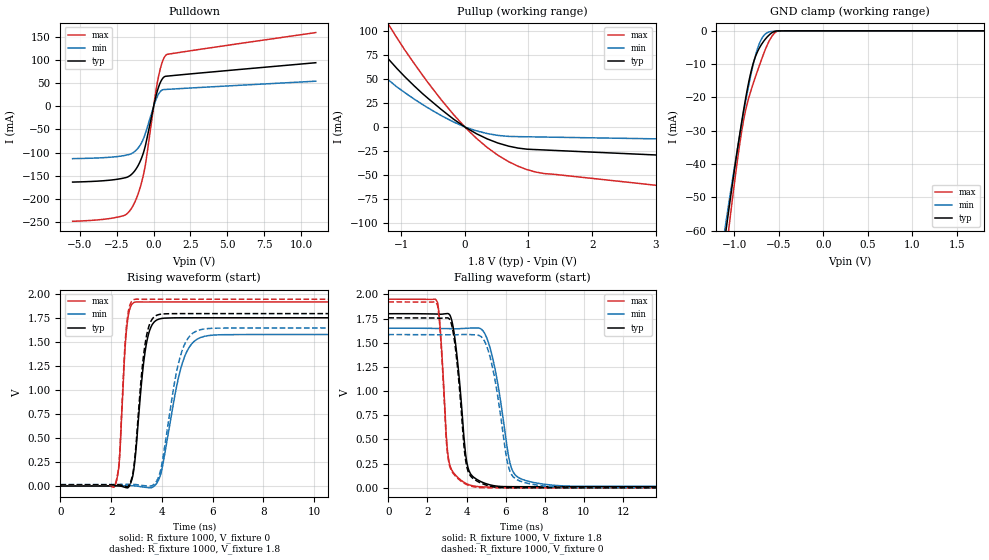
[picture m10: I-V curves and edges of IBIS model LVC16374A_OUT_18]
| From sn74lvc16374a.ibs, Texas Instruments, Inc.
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[Model]   LVC16374A_OUT_18
Model_type  3-state
Enable   Active-Low
Vref =   0
Rref =   1000
Cref =   30p
Vmeas =   0.9
| variable   typ   min   max
C_comp   5.26pF   4.69pF   6.09pF
| C_pullup   6.13pF   5.54pF   6.81pF
| C_pulldown   8.31pF   6.61pF   10.14pF
| C_tri-state   5.26pF   4.69pF   6.09pF
[Temperature Range]   40   100   -40
| Ambient temperature   25   85   -40
[Voltage range]   1.8   1.65   1.95
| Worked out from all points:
|   slope of the pulldown table from 0 to 0.27 V, typ, clamps not added: 7.65 ohm
|   slope of the pullup table from 0 to 0.27 V, typ, clamps not added: 27.4 ohm
|   GND clamp passes 1 mA (typ) near -0.60 V on its own axis
|   rising waveform, R_fixture 1000, V_fixture 0: 20-80 % time 371ps typ, 688ps min, 224ps max; typ from 0 V to 1.76 V
|   falling waveform, R_fixture 1000, V_fixture 1.8: 20-80 % time 474ps typ, 780ps min, 337ps max; typ from 1.8 V to 0.012 V
|   rising waveform, R_fixture 1000, V_fixture 1.8: 20-80 % time 357ps typ, 626ps min, 220ps max; typ from 0.012 V to 1.8 V
|   falling waveform, R_fixture 1000, V_fixture 0: 20-80 % time 458ps typ, 739ps min, 331ps max; typ from 1.76 V to 0 V
[GND Clamp]
| LVC16374A_OUT_18
|   Voltage   I(typ)   I(min)   I(max)
-5.5V     -1.092A    -985.9mA   -1.265A
-1.12V    -65.63mA   -62.5mA    -73.1mA
-1.09V    -59.68mA   -57.14mA   -66.23mA
-1.06V    -53.82mA   -51.86mA   -59.48mA
-1.045V   -50.92mA   -49.25mA   -56.15mA
-960mV    -35.13mA   -34.95mA   -38.34mA
-900mV    -24.87mA   -25.49mA   -27.8mA
-795mV    -10.66mA   -11.13mA   -16.59mA
-735mV    -6.119mA   -5.16mA    -11.82mA
-685mV    -3.765mA   -2.107mA   -8.076mA
-535mV    -84.46uA   -113.4uA   -414.9uA
1.8V      37.82pA    12.26nA    -2.547nA
[Pulldown]
| LVC16374A_OUT_18
|   Voltage   I(typ)   I(min)   I(max)
-5.5V     -163.6mA   -113mA     -248.3mA
-2.075V   -155.2mA   -106.7mA   -236.5mA
-1.745V   -152.2mA   -104.6mA   -230mA
-1.42V    -144.4mA   -100.5mA   -215.8mA
-1.03V    -126.4mA   -88.99mA   -186.9mA
-695mV    -100.2mA   -69.99mA   -148.2mA
-520mV    -79.1mA    -54.01mA   -118mA
70mV      10.47mA    6.993mA    15.91mA
275mV     35.8mA     23.13mA    55.48mA
565mV     58.22mA    35.03mA    93.73mA
855mV     65.08mA    36.56mA    111.2mA
11V       94.21mA    54.33mA    159.3mA
[Pullup]
| LVC16374A_OUT_18
|   Voltage   I(typ)   I(min)   I(max)
-5.5V     75.37mA    20.95mA    195.8mA
-3.75V    234.1mA    38.04mA    389.4mA
-3.41V    238.1mA    55.86mA    355.3mA
-3.285V   230.3mA    96.69mA    342mA
-3.205V   224.9mA    129.9mA    333.3mA
-2.375V   162.9mA    117.7mA    240.2mA
-1.61V    102.9mA    73.43mA    152.8mA
-1.185V   69.47mA    48.03mA    105.1mA
15mV      -631.9uA   -377.7uA   -1.037mA
1.115V    -23.53mA   -10.37mA   -46.86mA
8.41V     -45.64mA   -18.13mA   -100.6mA
11V       -53.91mA   -20.99mA   -120.6mA
[Ramp]
| LVC16374A_OUT_18
| variable   typ   min   max
dV/dt_r   1.07/3.78E-10   0.96/6.97E-10   1.16/2.34E-10
dV/dt_f   1.07/4.77E-10   0.98/7.83E-10   1.17/3.47E-10
R_load = 1000
[Rising Waveform]
| LVC16374A_OUT_18
R_fixture =   1000
C_fixture =   0
L_fixture =   0
V_fixture =   0
V_fixture_min = 0
V_fixture_max = 0
|   Time   V(typ)   V(min)   V(max)
0s        561.2pV    2.27nV     19.09nV
2.155ns   1.743mV    780.3uV    6.911mV
2.315ns   305.8uV    1.234mV    231.8mV
2.625ns   -19.15mV   2.172mV    1.679V
2.99ns    409.5mV    -214.5uV   1.922V
3.3ns     1.326V     -12.02mV   1.921V
3.61ns    1.681V     -15.78mV   1.921V
4.885ns   1.756V     1.342V     1.922V
5.865ns   1.756V     1.571V     1.922V
50ns      1.756V     1.582V     1.922V
[Falling Waveform]
| LVC16374A_OUT_18
R_fixture =   1000
C_fixture =   0
L_fixture =   0
V_fixture =   1.8
V_fixture_min = 1.65
V_fixture_max = 1.95
|   Time   V(typ)   V(min)   V(max)
0s        1.8V       1.65V      1.95V
2.5ns     1.797V     1.647V     1.923V
3.15ns    1.785V     1.646V     233.9mV
3.49ns    1.4V       1.645V     120.1mV
3.98ns    304.4mV    1.649V     44.69mV
4.36ns    110.5mV    1.653V     19.2mV
5.225ns   29.76mV    1.43V      8.825mV
6.32ns    12.32mV    191.9mV    8.431mV
7.58ns    11.7mV     49.38mV    8.364mV
50ns      11.53mV    15.73mV    8.262mV
[Rising Waveform]
| LVC16374A_OUT_18
R_fixture =   1000
C_fixture =   0
L_fixture =   0
V_fixture =   1.8
V_fixture_min = 1.65
V_fixture_max = 1.95
|   Time   V(typ)   V(min)   V(max)
0s        11.51mV    15.68mV    8.257mV
2.16ns    13.06mV    16.41mV    19.29mV
2.315ns   11.51mV    16.76mV    248.6mV
2.615ns   -6.588mV   17.43mV    1.7V
2.925ns   271.8mV    16.26mV    1.949V
3.27ns    1.345V     4.412mV    1.95V
3.565ns   1.718V     -1.06mV    1.95V
4.8ns     1.8V       1.414V     1.95V
5.7ns     1.8V       1.641V     1.95V
50ns      1.8V       1.65V      1.95V
[Falling Waveform]
| LVC16374A_OUT_18
R_fixture =   1000
C_fixture =   0
L_fixture =   0
V_fixture =   0
V_fixture_min = 0
V_fixture_max = 0
|   Time   V(typ)   V(min)   V(max)
0s        1.758V     1.585V     1.922V
2.5ns     1.755V     1.582V     1.894V
3.15ns    1.737V     1.582V     217.8mV
3.475ns   1.364V     1.582V     113.1mV
3.955ns   280.9mV    1.585V     38.37mV
4.36ns    92.59mV    1.582V     10.73mV
5.19ns    18.39mV    1.36V      570.1uV
6.22ns    861.3uV    170.9mV    184.7uV
7.47ns    192.5uV    32.78mV    106.9uV
50ns      12.28uV    45.74uV    5.027uV
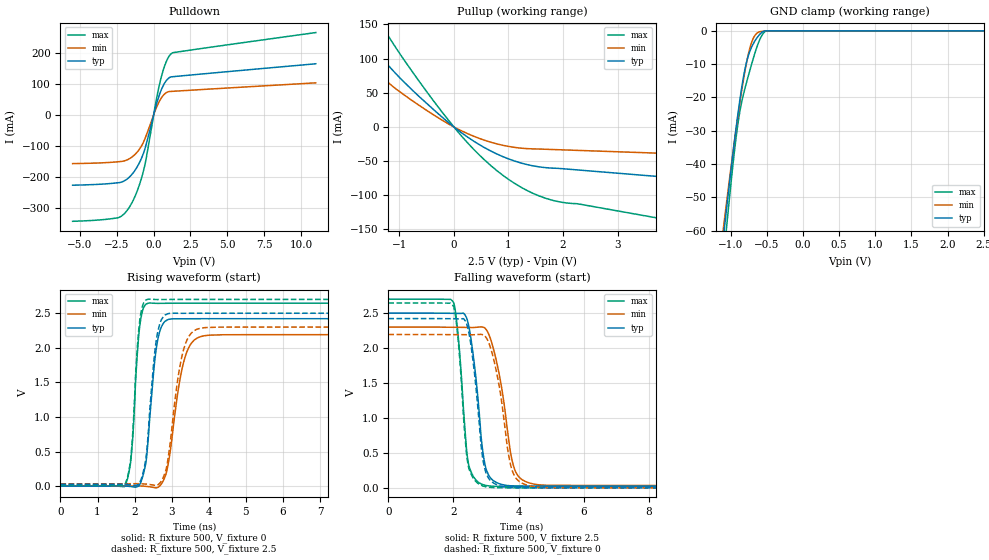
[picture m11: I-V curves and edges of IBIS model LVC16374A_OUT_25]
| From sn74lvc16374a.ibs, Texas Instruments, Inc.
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[Model]   LVC16374A_OUT_25
Model_type  3-state
Enable   Active-Low
Vref =   0
Rref =   500
Cref =   30p
Vmeas =   1.25
| variable   typ   min   max
C_comp   5.07pF   4.45pF   6.04pF
| C_pullup   6.01pF   5.36pF   6.86pF
| C_pulldown   7.61pF   6.28pF   8.94pF
| C_tri-state   5.07pF   4.45pF   6.04pF
[Temperature Range]   40   100   -40
| Ambient temperature   25   85   -40
[Voltage range]   2.5   2.3   2.7
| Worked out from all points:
|   slope of the pulldown table from 0 to 0.375 V, typ, clamps not added: 6 ohm
|   slope of the pullup table from 0 to 0.375 V, typ, clamps not added: 17.5 ohm
|   GND clamp passes 1 mA (typ) near -0.60 V on its own axis
|   rising waveform, R_fixture 500, V_fixture 0: 20-80 % time 236ps typ, 361ps min, 177ps max; typ from 0 V to 2.42 V
|   falling waveform, R_fixture 500, V_fixture 2.5: 20-80 % time 326ps typ, 457ps min, 254ps max; typ from 2.5 V to 0.025 V
|   rising waveform, R_fixture 500, V_fixture 2.5: 20-80 % time 229ps typ, 338ps min, 174ps max; typ from 0.025 V to 2.5 V
|   falling waveform, R_fixture 500, V_fixture 0: 20-80 % time 313ps typ, 429ps min, 250ps max; typ from 2.42 V to 0 V
[GND Clamp]
| LVC16374A_OUT_25
|   Voltage   I(typ)   I(min)   I(max)
-5.5V     -1.092A    -985.9mA   -1.265A
-1.115V   -64.63mA   -61.6mA    -71.95mA
-1.085V   -58.69mA   -56.25mA   -65.09mA
-1.055V   -52.85mA   -50.99mA   -58.36mA
-905mV    -25.68mA   -26.25mA   -28.57mA
-860mV    -18.71mA   -19.61mA   -22.6mA
-795mV    -10.66mA   -11.13mA   -16.59mA
-740mV    -6.406mA   -5.567mA   -12.21mA
-680mV    -3.568mA   -1.9mA     -7.713mA
-600mV    -1.079mA   -275.4uA   -2.703mA
-530mV    -59.09uA   -106.9uA   -320.1uA
2.5V      50.37pA    32.07nA    -2.817nA
[Pulldown]
| LVC16374A_OUT_25
|   Voltage   I(typ)   I(min)   I(max)
-5.5V     -227.2mA   -157.4mA   -343.8mA
-2.435V   -219.3mA   -151.6mA   -332.5mA
-2V       -213.4mA   -148.8mA   -319.6mA
-1.575V   -197.6mA   -139.6mA   -292.6mA
-1.075V   -164.4mA   -117.7mA   -240.6mA
-650mV    -118.1mA   -83.84mA   -173.1mA
-495mV    -93.12mA   -65.26mA   -137.4mA
185mV     33.61mA    23.27mA    50.14mA
545mV     83.64mA    56.25mA    127.2mA
875mV     111.7mA    72.29mA    173.9mA
1.21V     122.9mA    75.8mA     198.2mA
11V       165.1mA    103.4mA    265.9mA
[Pullup]
| LVC16374A_OUT_25
|   Voltage   I(typ)   I(min)   I(max)
-5.5V     443.1mA    133.6mA    676.2mA
-5.3V     442mA      146.1mA    654.8mA
-2.67V    223.9mA    166.9mA    324.6mA
-2.115V   173mA      128.2mA    251.7mA
-1.69V    134.3mA    98.74mA    196.2mA
-1.285V   97.35mA    70.47mA    143.5mA
-360mV    24.51mA    17.05mA    36.8mA
465mV     -25.84mA   -16.77mA   -40.96mA
1.11V     -49.84mA   -29.91mA   -82.48mA
1.855V    -60.43mA   -33.17mA   -108.3mA
4.49V     -77.42mA   -40.47mA   -144.1mA
11V       -121.1mA   -58.83mA   -239.8mA
[Ramp]
| LVC16374A_OUT_25
| variable   typ   min   max
dV/dt_r   1.46/2.45E-10   1.33/3.72E-10   1.59/1.82E-10
dV/dt_f   1.48/3.33E-10   1.36/4.64E-10   1.61/2.58E-10
R_load = 500
[Rising Waveform]
| LVC16374A_OUT_25
R_fixture =   500
C_fixture =   0
L_fixture =   0
V_fixture =   0
V_fixture_min = 0
V_fixture_max = 0
|   Time   V(typ)   V(min)   V(max)
0s        617.4pV    1.958nV    18.26nV
1.75ns    897.3uV    1.171mV    18.97mV
1.915ns   -7.342mV   1.787mV    473.3mV
2.145ns   32.42mV    2.028mV    2.345V
2.39ns    856mV      -8.428mV   2.648V
2.56ns    1.894V     -23.88mV   2.643V
2.73ns    2.314V     38.94mV    2.643V
3.37ns    2.42V      1.884V     2.645V
3.995ns   2.421V     2.182V     2.645V
50ns      2.421V     2.19V      2.645V
[Falling Waveform]
| LVC16374A_OUT_25
R_fixture =   500
C_fixture =   0
L_fixture =   0
V_fixture =   2.5
V_fixture_min = 2.3
V_fixture_max = 2.7
|   Time   V(typ)   V(min)   V(max)
0s        2.5V       2.3V       2.7V
2.01ns    2.497V     2.297V     2.645V
2.165ns   2.495V     2.297V     2.076V
2.365ns   2.468V     2.296V     770.8mV
2.56ns    2.063V     2.293V     208.7mV
2.9ns     529.7mV    2.3V       47.33mV
3.1ns     166.1mV    2.181V     27.46mV
3.87ns    27.87mV    279.2mV    19mV
4.635ns   25.89mV    42.89mV    18.74mV
50ns      25.46mV    33.49mV    18.58mV
[Rising Waveform]
| LVC16374A_OUT_25
R_fixture =   500
C_fixture =   0
L_fixture =   0
V_fixture =   2.5
V_fixture_min = 2.3
V_fixture_max = 2.7
|   Time   V(typ)   V(min)   V(max)
0s        25.45mV    33.45mV    18.57mV
1.75ns    26.01mV    34.45mV    38.61mV
1.91ns    18.25mV    34.89mV    485.7mV
2.14ns    56.04mV    34.91mV    2.404V
2.385ns   914.3mV    24.78mV    2.704V
2.555ns   1.996V     11.24mV    2.699V
2.72ns    2.405V     72.4mV     2.698V
3.32ns    2.499V     1.975V     2.7V
3.895ns   2.5V       2.292V     2.7V
50ns      2.5V       2.3V       2.7V
[Falling Waveform]
| LVC16374A_OUT_25
R_fixture =   500
C_fixture =   0
L_fixture =   0
V_fixture =   0
V_fixture_min = 0
V_fixture_max = 0
|   Time   V(typ)   V(min)   V(max)
0s        2.422V     2.194V     2.646V
2.005ns   2.42V      2.192V     2.594V
2.16ns    2.418V     2.192V     2.034V
2.355ns   2.394V     2.191V     735.2mV
2.555ns   1.983V     2.19V      185.1mV
2.88ns    485.6mV    2.193V     30.9mV
3.095ns   127.9mV    2.065V     8.669mV
3.805ns   2.696mV    248.1mV    473.3uV
4.595ns   417.5uV    8.093mV    166.2uV
50ns      9.807uV    35.5uV     3.907uV
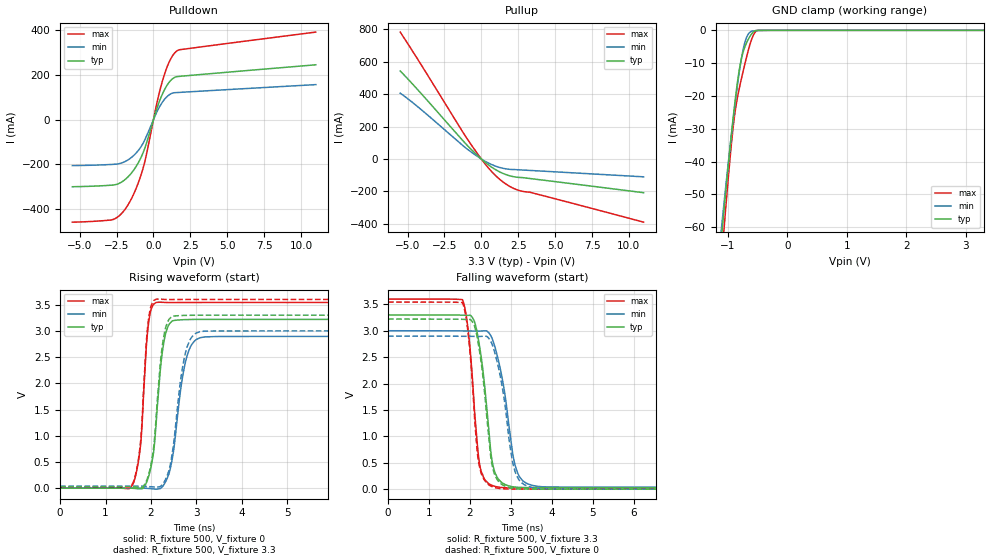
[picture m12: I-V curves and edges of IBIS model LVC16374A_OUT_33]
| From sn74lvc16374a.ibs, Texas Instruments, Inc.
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[Model]   LVC16374A_OUT_33
Model_type  3-state
Enable   Active-Low
Vref =   0
Rref =   500
Cref =   50p
Vmeas =   1.5
| variable   typ   min   max
C_comp   4.90pF   4.27pF   6.01pF
| C_pullup   5.95pF   5.18pF   6.99pF
| C_pulldown   7.16pF   5.94pF   8.13pF
| C_tri-state   4.90pF   4.27pF   6.01pF
[Temperature Range]   40   100   -40
| Ambient temperature   25   85   -40
[Voltage range]   3.3   3   3.6
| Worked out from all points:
|   slope of the pulldown table from 0 to 0.495 V, typ, clamps not added: 5.09 ohm
|   slope of the pullup table from 0 to 0.495 V, typ, clamps not added: 13.3 ohm
|   GND clamp passes 1 mA (typ) near -0.60 V on its own axis
|   rising waveform, R_fixture 500, V_fixture 0: 20-80 % time 197ps typ, 265ps min, 155ps max; typ from 0 V to 3.22 V
|   falling waveform, R_fixture 500, V_fixture 3.3: 20-80 % time 267ps typ, 350ps min, 220ps max; typ from 3.3 V to 0.029 V
|   rising waveform, R_fixture 500, V_fixture 3.3: 20-80 % time 196ps typ, 255ps min, 155ps max; typ from 0.029 V to 3.3 V
|   falling waveform, R_fixture 500, V_fixture 0: 20-80 % time 262ps typ, 336ps min, 206ps max; typ from 3.22 V to 0 V
[GND Clamp]
| LVC16374A_OUT_33
|   Voltage   I(typ)   I(min)   I(max)
-5.5V     -1.092A    -985.9mA   -1.265A
-1.13V    -67.63mA   -64.3mA    -75.42mA
-1.095V   -60.66mA   -58.03mA   -67.37mA
-1.065V   -54.79mA   -52.74mA   -60.59mA
-910mV    -26.51mA   -27.02mA   -29.36mA
-865mV    -19.44mA   -20.32mA   -23.16mA
-795mV    -10.66mA   -11.13mA   -16.59mA
-740mV    -6.406mA   -5.567mA   -12.21mA
-680mV    -3.568mA   -1.9mA     -7.713mA
-600mV    -1.079mA   -275.4uA   -2.703mA
-520mV    -35.47uA   -95.17uA   -168.9uA
3.3V      64.71pA    54.7nA     -3.114nA
[Pulldown]
| LVC16374A_OUT_33
|   Voltage   I(typ)   I(min)   I(max)
-5.5V     -300mA     -205.4mA   -458.6mA
-2.76V    -292.7mA   -199.9mA   -447mA
-2.24V    -282mA     -195.3mA   -425mA
-1.72V    -255.5mA   -179.7mA   -380.4mA
-1.16V    -207.6mA   -148.1mA   -305.1mA
-670mV    -142.6mA   -101.5mA   -209.1mA
-500mV    -110.4mA   -77.62mA   -163.1mA
255mV     54.31mA    37.86mA    80.86mA
710mV     129mA      87.77mA    195.2mA
1.135V    173mA      114mA      267.3mA
1.56V     192.2mA    121.2mA    306.1mA
11V       245.5mA    156.8mA    391.8mA
[Pullup]
| LVC16374A_OUT_33
|   Voltage   I(typ)   I(min)   I(max)
-5.5V     543.3mA    406.3mA    783.2mA
-4.16V    412.1mA    311.1mA    592.9mA
-1.405V   128.8mA    95.07mA    187.7mA
-805mV    70.25mA    51.09mA    103.8mA
370mV     -28.42mA   -19.63mA   -43.35mA
890mV     -61.47mA   -41.24mA   -95.52mA
1.405V    -86.3mA    -55.79mA   -137.1mA
1.995V    -105.1mA   -64.06mA   -172.4mA
2.59V     -113.6mA   -66.71mA   -194.7mA
3.25V     -119.7mA   -70.05mA   -203.9mA
11V       -207.7mA   -109.8mA   -389.6mA
[Ramp]
| LVC16374A_OUT_33
| variable   typ   min   max
dV/dt_r   1.94/2.05E-10   1.75/2.77E-10   2.13/1.63E-10
dV/dt_f   1.96/2.71E-10   1.78/3.56E-10   2.15/2.27E-10
R_load = 500
[Rising Waveform]
| LVC16374A_OUT_33
R_fixture =   500
C_fixture =   0
L_fixture =   0
V_fixture =   0
V_fixture_min = 0
V_fixture_max = 0
|   Time   V(typ)   V(min)   V(max)
0s        790.9pV    1.869nV    18.83nV
1.605ns   -2.554mV   1.911mV    81.57mV
1.775ns   -11.74mV   1.936mV    845.7mV
1.945ns   211.4mV    -5.733mV   3.124V
2.13ns    1.432V     -18.36mV   3.545V
2.25ns    2.585V     26.11mV    3.545V
2.39ns    3.109V     257.7mV    3.541V
2.78ns    3.216V     2.473V     3.542V
3.2ns     3.22V      2.886V     3.542V
50ns      3.22V      2.895V     3.542V
[Falling Waveform]
| LVC16374A_OUT_33
R_fixture =   500
C_fixture =   0
L_fixture =   0
V_fixture =   3.3
V_fixture_min = 3
V_fixture_max = 3.6
|   Time   V(typ)   V(min)   V(max)
0s        3.3V       3V         3.6V
1.815ns   3.295V     2.997V     3.59V
1.97ns    3.292V     2.996V     2.915V
2.11ns    3.174V     2.994V     1.503V
2.255ns   2.604V     2.994V     395.4mV
2.54ns    539mV      2.855V     72.04mV
2.78ns    123.4mV    2.127V     30.83mV
3.16ns    35.72mV    318.5mV    22.22mV
3.78ns    29.23mV    44.42mV    21.35mV
50ns      28.59mV    36.92mV    21.11mV
[Rising Waveform]
| LVC16374A_OUT_33
R_fixture =   500
C_fixture =   0
L_fixture =   0
V_fixture =   3.3
V_fixture_min = 3
V_fixture_max = 3.6
|   Time   V(typ)   V(min)   V(max)
0s        28.58mV    36.89mV    21.11mV
1.605ns   25.81mV    38.57mV    104.3mV
1.775ns   17.31mV    38.38mV    907mV
1.945ns   248.1mV    30.7mV     3.205V
2.13ns    1.549V     19.25mV    3.607V
2.25ns    2.707V     67.22mV    3.603V
2.385ns   3.199V     303.5mV    3.599V
2.765ns   3.296V     2.595V     3.6V
3.175ns   3.3V       2.994V     3.6V
50ns      3.3V       3V         3.6V
[Falling Waveform]
| LVC16374A_OUT_33
R_fixture =   500
C_fixture =   0
L_fixture =   0
V_fixture =   0
V_fixture_min = 0
V_fixture_max = 0
|   Time   V(typ)   V(min)   V(max)
0s        3.221V     2.898V     3.543V
1.815ns   3.217V     2.895V     3.533V
1.97ns    3.213V     2.895V     2.846V
2.17ns    2.901V     2.893V     774.4mV
2.225ns   2.657V     2.892V     451.1mV
2.525ns   523.5mV    2.773V     53.99mV
2.775ns   91.22mV    1.994V     9.264mV
3.115ns   8.962mV    304.1mV    1.262mV
3.765ns   591.8uV    6.319mV    240.4uV
50ns      9.824uV    37.26uV    3.55uV
